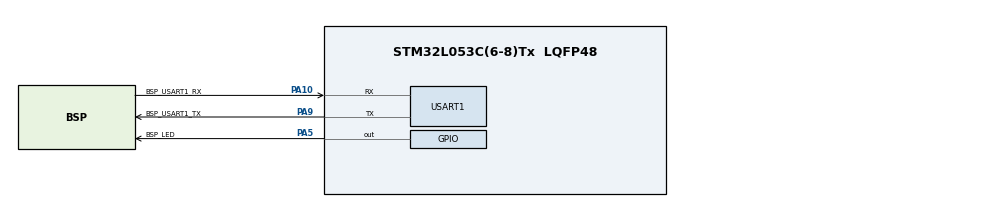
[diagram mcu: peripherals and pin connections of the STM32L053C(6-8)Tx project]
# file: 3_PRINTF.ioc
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Mcu.Family=STM32L0
Mcu.Name=STM32L053C(6-8)Tx
Mcu.Package=LQFP48
PA10.GPIO_Label=BSP_USART1_RX
PA10.Mode=Asynchronous
PA10.Signal=USART1_RX
PA5.GPIO_Label=BSP_LED
PA5.Signal=GPIO_Output
PA9.GPIO_Label=BSP_USART1_TX
PA9.Mode=Asynchronous
PA9.Signal=USART1_TX
ProjectManager.HeapSize=0x200
ProjectManager.StackSize=0x400
ProjectManager.TargetToolchain=STM32CubeIDE
RCC.AHBFreq_Value=16000000
RCC.APB1CLKDivider=RCC_HCLK_DIV2
RCC.APB1Freq_Value=8000000
RCC.APB1TimFreq_Value=16000000
RCC.APB2Freq_Value=16000000
RCC.APB2TimFreq_Value=16000000
RCC.HCLKFreq_Value=16000000
RCC.HSE_VALUE=8000000
RCC.HSI16_VALUE=16000000
RCC.HSI48MClockSelection=RCC_USBCLKSOURCE_HSI48
RCC.HSI48_VALUE=48000000
RCC.HSI_VALUE=16000000
RCC.LSE_VALUE=32768
RCC.MSI_VALUE=2097000
RCC.PLLDIV=RCC_PLLDIV_3
RCC.RTCClockSelectionVirtual=RCC_RTCCLKSOURCE_LSE
RCC.SYSCLKFreq_VALUE=16000000
RCC.SYSCLKSource=RCC_SYSCLKSOURCE_PLLCLK
RCC.VCOOutputFreq_Value=48000000
USART1.VirtualMode-Asynchronous=VM_ASYNC
board=STM32L0538-DISCO

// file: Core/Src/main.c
/* USER CODE BEGIN Header */
/**
  ******************************************************************************
  * @file           : main.c
  * @brief          : Main program body
  ******************************************************************************
  * @attention
  *
  * Copyright (c) 2024 STMicroelectronics.
  * All rights reserved.
  *
  * This software is licensed under terms that can be found in the LICENSE file
  * in the root directory of this software component.
  * If no LICENSE file comes with this software, it is provided AS-IS.
  *
  ******************************************************************************
  */
/* USER CODE END Header */
#include "main.h"
#include "stdio.h"

UART_HandleTypeDef huart1;

void SystemClock_Config(void);
static void MX_GPIO_Init(void);
static void MX_USART1_UART_Init(void);

int main(void)
{

  /* MCU Configuration--------------------------------------------------------*/

  /* Reset of all peripherals, Initializes the Flash interface and the Systick. */
  HAL_Init();

  /* Configure the system clock */
  SystemClock_Config();

  /* Initialize all configured peripherals */
  MX_GPIO_Init();
  MX_USART1_UART_Init();

  /* Infinite loop */
  while (1)
  {

    /* USER CODE BEGIN 3 */
//	  HAL_UART_Transmit(&huart1, tx_msg , 20, 100);
//	  HAL_UART_Transmit(&huart1, tx_msg , 20, 100);
	  printf("Hello From Main.c\r\n");
//	  HAL_Delay(1000);

  }
  /* USER CODE END 3 */
}

void SystemClock_Config(void)
{
  RCC_OscInitTypeDef RCC_OscInitStruct = {0};
  RCC_ClkInitTypeDef RCC_ClkInitStruct = {0};
  RCC_PeriphCLKInitTypeDef PeriphClkInit = {0};

  /** Configure the main internal regulator output voltage
  */
  __HAL_PWR_VOLTAGESCALING_CONFIG(PWR_REGULATOR_VOLTAGE_SCALE1);

  /** Initializes the RCC Oscillators according to the specified parameters
  * in the RCC_OscInitTypeDef structure.
  */
  RCC_OscInitStruct.OscillatorType = RCC_OSCILLATORTYPE_HSI;
  RCC_OscInitStruct.HSIState = RCC_HSI_ON;
  RCC_OscInitStruct.HSICalibrationValue = RCC_HSICALIBRATION_DEFAULT;
  RCC_OscInitStruct.PLL.PLLState = RCC_PLL_ON;
  RCC_OscInitStruct.PLL.PLLSource = RCC_PLLSOURCE_HSI;
  RCC_OscInitStruct.PLL.PLLMUL = RCC_PLLMUL_3;
  RCC_OscInitStruct.PLL.PLLDIV = RCC_PLLDIV_3;
  if (HAL_RCC_OscConfig(&RCC_OscInitStruct) != HAL_OK)
  {
    Error_Handler();
  }

  /** Initializes the CPU, AHB and APB buses clocks
  */
  RCC_ClkInitStruct.ClockType = RCC_CLOCKTYPE_HCLK|RCC_CLOCKTYPE_SYSCLK
                              |RCC_CLOCKTYPE_PCLK1|RCC_CLOCKTYPE_PCLK2;
  RCC_ClkInitStruct.SYSCLKSource = RCC_SYSCLKSOURCE_PLLCLK;
  RCC_ClkInitStruct.AHBCLKDivider = RCC_SYSCLK_DIV1;
  RCC_ClkInitStruct.APB1CLKDivider = RCC_HCLK_DIV1;
  RCC_ClkInitStruct.APB2CLKDivider = RCC_HCLK_DIV1;

  if (HAL_RCC_ClockConfig(&RCC_ClkInitStruct, FLASH_LATENCY_0) != HAL_OK)
  {
    Error_Handler();
  }
  PeriphClkInit.PeriphClockSelection = RCC_PERIPHCLK_USART1;
  PeriphClkInit.Usart1ClockSelection = RCC_USART1CLKSOURCE_PCLK2;
  if (HAL_RCCEx_PeriphCLKConfig(&PeriphClkInit) != HAL_OK)
  {
    Error_Handler();
  }
}

static void MX_USART1_UART_Init(void)
{

  huart1.Instance = USART1;
  huart1.Init.BaudRate = 115200;
  huart1.Init.WordLength = UART_WORDLENGTH_8B;
  huart1.Init.StopBits = UART_STOPBITS_1;
  huart1.Init.Parity = UART_PARITY_NONE;
  huart1.Init.Mode = UART_MODE_TX_RX;
  huart1.Init.HwFlowCtl = UART_HWCONTROL_NONE;
  huart1.Init.OverSampling = UART_OVERSAMPLING_16;
  huart1.Init.OneBitSampling = UART_ONE_BIT_SAMPLE_DISABLE;
  huart1.AdvancedInit.AdvFeatureInit = UART_ADVFEATURE_NO_INIT;
  if (HAL_UART_Init(&huart1) != HAL_OK)
  {
    Error_Handler();
  }

}

static void MX_GPIO_Init(void)
{
  GPIO_InitTypeDef GPIO_InitStruct = {0};

  /* GPIO Ports Clock Enable */
  __HAL_RCC_GPIOA_CLK_ENABLE();

  /*Configure GPIO pin Output Level */
  HAL_GPIO_WritePin(BSP_LED_GPIO_Port, BSP_LED_Pin, GPIO_PIN_RESET);

  /*Configure GPIO pin : BSP_LED_Pin */
  GPIO_InitStruct.Pin = BSP_LED_Pin;
  GPIO_InitStruct.Mode = GPIO_MODE_OUTPUT_PP;
  GPIO_InitStruct.Pull = GPIO_NOPULL;
  GPIO_InitStruct.Speed = GPIO_SPEED_FREQ_LOW;
  HAL_GPIO_Init(BSP_LED_GPIO_Port, &GPIO_InitStruct);

}

void Error_Handler(void)
{
  __disable_irq();
  while (1)
  {
  }
}
